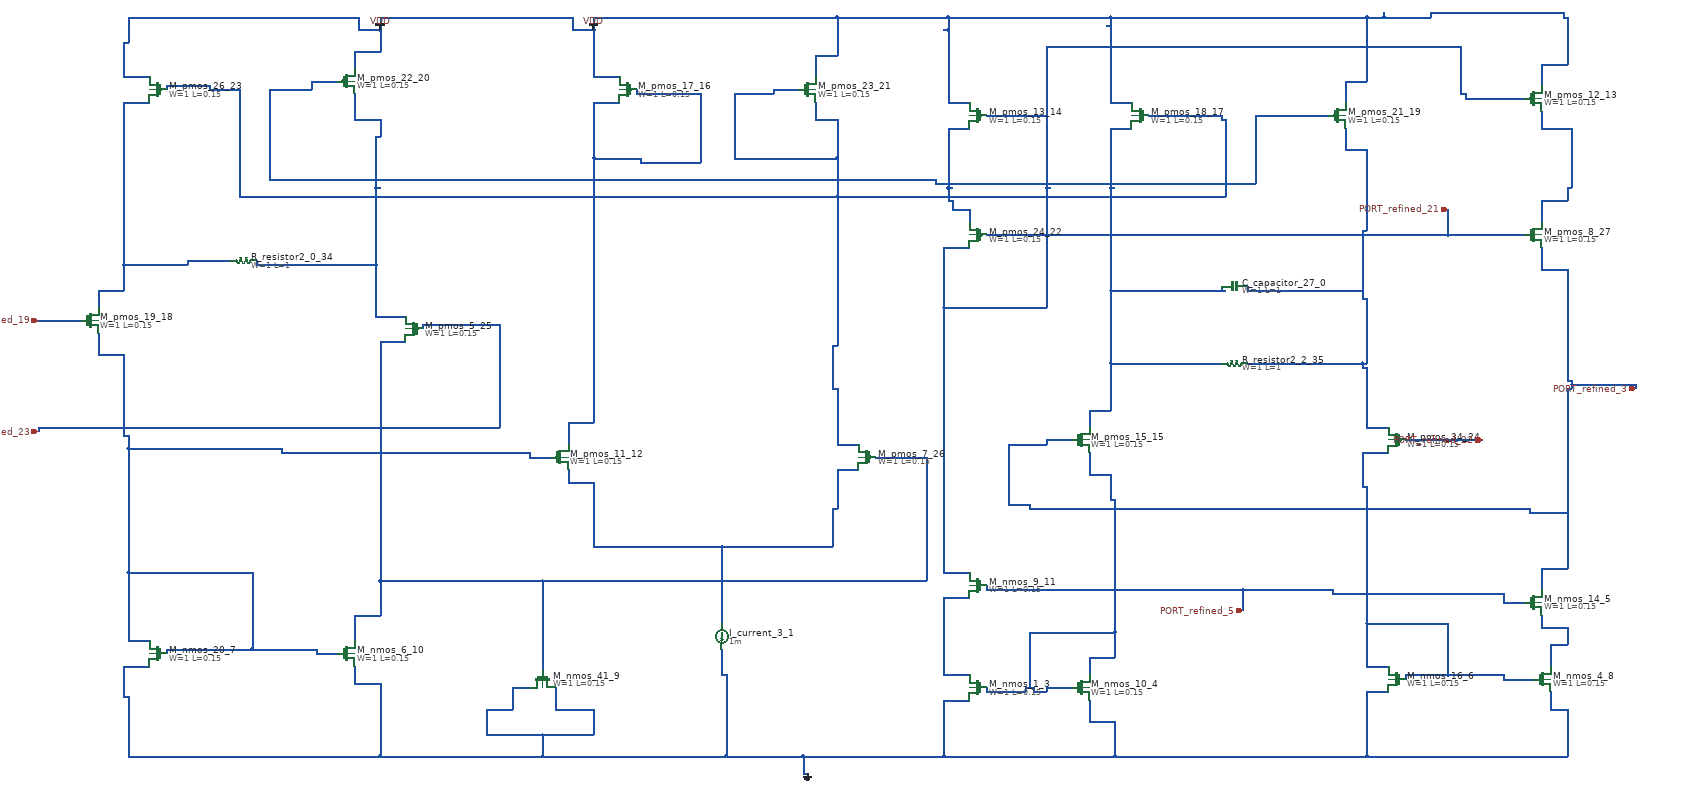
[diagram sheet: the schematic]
v {xschem version=3.4.8 file_version=1.2}
G {}
K {}
V {}
S {}
E {}
C {sky130_fd_pr/cap_mim_m3_1.sym} 2920 760 1 0 {name="C_capacitor_27_0" model=cap_mim_m3_1 W=1 L=1 MF=1 spiceprefix=X}
C {devices/isource.sym} 1720 1580 0 0 {name="I_current_3_1" value=1m}
C {devices/gnd.sym} 1920 1900 0 0 {name="l_gnd_28_2" lab="GND"}
C {sky130_fd_pr/nfet3_01v8.sym} 2320 1700 0 1 {name="M_nmos_1_3"
W=1
L=0.15
body=GND
nf=1
mult=1
ad="expr('int((@nf + 1)/2) * @W / @nf * 0.29')"
pd="expr('2*int((@nf + 1)/2) * (@W / @nf + 0.29)')"
as="expr('int((@nf + 2)/2) * @W / @nf * 0.29')"
ps="expr('2*int((@nf + 2)/2) * (@W / @nf + 0.29)')"
nrd="expr('0.29 / @W ')" nrs="expr('0.29 / @W ')"
sa=0 sb=0 sd=0
model=nfet_01v8
spiceprefix=X
}
C {sky130_fd_pr/nfet3_01v8.sym} 2560 1700 0 0 {name="M_nmos_10_4"
W=1
L=0.15
body=GND
nf=1
mult=1
ad="expr('int((@nf + 1)/2) * @W / @nf * 0.29')"
pd="expr('2*int((@nf + 1)/2) * (@W / @nf + 0.29)')"
as="expr('int((@nf + 2)/2) * @W / @nf * 0.29')"
ps="expr('2*int((@nf + 2)/2) * (@W / @nf + 0.29)')"
nrd="expr('0.29 / @W ')" nrs="expr('0.29 / @W ')"
sa=0 sb=0 sd=0
model=nfet_01v8
spiceprefix=X
}
C {sky130_fd_pr/nfet3_01v8.sym} 3620 1500 0 0 {name="M_nmos_14_5"
W=1
L=0.15
body=GND
nf=1
mult=1
ad="expr('int((@nf + 1)/2) * @W / @nf * 0.29')"
pd="expr('2*int((@nf + 1)/2) * (@W / @nf + 0.29)')"
as="expr('int((@nf + 2)/2) * @W / @nf * 0.29')"
ps="expr('2*int((@nf + 2)/2) * (@W / @nf + 0.29)')"
nrd="expr('0.29 / @W ')" nrs="expr('0.29 / @W ')"
sa=0 sb=0 sd=0
model=nfet_01v8
spiceprefix=X
}
C {sky130_fd_pr/nfet3_01v8.sym} 3300 1680 0 1 {name="M_nmos_16_6"
W=1
L=0.15
body=GND
nf=1
mult=1
ad="expr('int((@nf + 1)/2) * @W / @nf * 0.29')"
pd="expr('2*int((@nf + 1)/2) * (@W / @nf + 0.29)')"
as="expr('int((@nf + 2)/2) * @W / @nf * 0.29')"
ps="expr('2*int((@nf + 2)/2) * (@W / @nf + 0.29)')"
nrd="expr('0.29 / @W ')" nrs="expr('0.29 / @W ')"
sa=0 sb=0 sd=0
model=nfet_01v8
spiceprefix=X
}
C {sky130_fd_pr/nfet3_01v8.sym} 400 1620 0 1 {name="M_nmos_20_7"
W=1
L=0.15
body=GND
nf=1
mult=1
ad="expr('int((@nf + 1)/2) * @W / @nf * 0.29')"
pd="expr('2*int((@nf + 1)/2) * (@W / @nf + 0.29)')"
as="expr('int((@nf + 2)/2) * @W / @nf * 0.29')"
ps="expr('2*int((@nf + 2)/2) * (@W / @nf + 0.29)')"
nrd="expr('0.29 / @W ')" nrs="expr('0.29 / @W ')"
sa=0 sb=0 sd=0
model=nfet_01v8
spiceprefix=X
}
C {sky130_fd_pr/nfet3_01v8.sym} 3640 1680 0 0 {name="M_nmos_4_8"
W=1
L=0.15
body=GND
nf=1
mult=1
ad="expr('int((@nf + 1)/2) * @W / @nf * 0.29')"
pd="expr('2*int((@nf + 1)/2) * (@W / @nf + 0.29)')"
as="expr('int((@nf + 2)/2) * @W / @nf * 0.29')"
ps="expr('2*int((@nf + 2)/2) * (@W / @nf + 0.29)')"
nrd="expr('0.29 / @W ')" nrs="expr('0.29 / @W ')"
sa=0 sb=0 sd=0
model=nfet_01v8
spiceprefix=X
}
C {sky130_fd_pr/nfet3_01v8.sym} 1300 1680 1 0 {name="M_nmos_41_9"
W=1
L=0.15
body=GND
nf=1
mult=1
ad="expr('int((@nf + 1)/2) * @W / @nf * 0.29')"
pd="expr('2*int((@nf + 1)/2) * (@W / @nf + 0.29)')"
as="expr('int((@nf + 2)/2) * @W / @nf * 0.29')"
ps="expr('2*int((@nf + 2)/2) * (@W / @nf + 0.29)')"
nrd="expr('0.29 / @W ')" nrs="expr('0.29 / @W ')"
sa=0 sb=0 sd=0
model=nfet_01v8
spiceprefix=X
}
C {sky130_fd_pr/nfet3_01v8.sym} 840 1620 0 0 {name="M_nmos_6_10"
W=1
L=0.15
body=GND
nf=1
mult=1
ad="expr('int((@nf + 1)/2) * @W / @nf * 0.29')"
pd="expr('2*int((@nf + 1)/2) * (@W / @nf + 0.29)')"
as="expr('int((@nf + 2)/2) * @W / @nf * 0.29')"
ps="expr('2*int((@nf + 2)/2) * (@W / @nf + 0.29)')"
nrd="expr('0.29 / @W ')" nrs="expr('0.29 / @W ')"
sa=0 sb=0 sd=0
model=nfet_01v8
spiceprefix=X
}
C {sky130_fd_pr/nfet3_01v8.sym} 2320 1460 0 1 {name="M_nmos_9_11"
W=1
L=0.15
body=GND
nf=1
mult=1
ad="expr('int((@nf + 1)/2) * @W / @nf * 0.29')"
pd="expr('2*int((@nf + 1)/2) * (@W / @nf + 0.29)')"
as="expr('int((@nf + 2)/2) * @W / @nf * 0.29')"
ps="expr('2*int((@nf + 2)/2) * (@W / @nf + 0.29)')"
nrd="expr('0.29 / @W ')" nrs="expr('0.29 / @W ')"
sa=0 sb=0 sd=0
model=nfet_01v8
spiceprefix=X
}
C {sky130_fd_pr/pfet3_01v8.sym} 1340 1160 0 0 {name="M_pmos_11_12"
W=1
L=0.15
body=VDD
nf=1
mult=1
ad="expr('int((@nf + 1)/2) * @W / @nf * 0.29')"
pd="expr('2*int((@nf + 1)/2) * (@W / @nf + 0.29)')"
as="expr('int((@nf + 2)/2) * @W / @nf * 0.29')"
ps="expr('2*int((@nf + 2)/2) * (@W / @nf + 0.29)')"
nrd="expr('0.29 / @W ')" nrs="expr('0.29 / @W ')"
sa=0 sb=0 sd=0
model=pfet_01v8
spiceprefix=X
}
C {sky130_fd_pr/pfet3_01v8.sym} 3620 320 0 0 {name="M_pmos_12_13"
W=1
L=0.15
body=VDD
nf=1
mult=1
ad="expr('int((@nf + 1)/2) * @W / @nf * 0.29')"
pd="expr('2*int((@nf + 1)/2) * (@W / @nf + 0.29)')"
as="expr('int((@nf + 2)/2) * @W / @nf * 0.29')"
ps="expr('2*int((@nf + 2)/2) * (@W / @nf + 0.29)')"
nrd="expr('0.29 / @W ')" nrs="expr('0.29 / @W ')"
sa=0 sb=0 sd=0
model=pfet_01v8
spiceprefix=X
}
C {sky130_fd_pr/pfet3_01v8.sym} 2320 360 0 1 {name="M_pmos_13_14"
W=1
L=0.15
body=VDD
nf=1
mult=1
ad="expr('int((@nf + 1)/2) * @W / @nf * 0.29')"
pd="expr('2*int((@nf + 1)/2) * (@W / @nf + 0.29)')"
as="expr('int((@nf + 2)/2) * @W / @nf * 0.29')"
ps="expr('2*int((@nf + 2)/2) * (@W / @nf + 0.29)')"
nrd="expr('0.29 / @W ')" nrs="expr('0.29 / @W ')"
sa=0 sb=0 sd=0
model=pfet_01v8
spiceprefix=X
}
C {sky130_fd_pr/pfet3_01v8.sym} 2560 1120 0 0 {name="M_pmos_15_15"
W=1
L=0.15
body=VDD
nf=1
mult=1
ad="expr('int((@nf + 1)/2) * @W / @nf * 0.29')"
pd="expr('2*int((@nf + 1)/2) * (@W / @nf + 0.29)')"
as="expr('int((@nf + 2)/2) * @W / @nf * 0.29')"
ps="expr('2*int((@nf + 2)/2) * (@W / @nf + 0.29)')"
nrd="expr('0.29 / @W ')" nrs="expr('0.29 / @W ')"
sa=0 sb=0 sd=0
model=pfet_01v8
spiceprefix=X
}
C {sky130_fd_pr/pfet3_01v8.sym} 1500 300 0 1 {name="M_pmos_17_16"
W=1
L=0.15
body=VDD
nf=1
mult=1
ad="expr('int((@nf + 1)/2) * @W / @nf * 0.29')"
pd="expr('2*int((@nf + 1)/2) * (@W / @nf + 0.29)')"
as="expr('int((@nf + 2)/2) * @W / @nf * 0.29')"
ps="expr('2*int((@nf + 2)/2) * (@W / @nf + 0.29)')"
nrd="expr('0.29 / @W ')" nrs="expr('0.29 / @W ')"
sa=0 sb=0 sd=0
model=pfet_01v8
spiceprefix=X
}
C {sky130_fd_pr/pfet3_01v8.sym} 2700 360 0 1 {name="M_pmos_18_17"
W=1
L=0.15
body=VDD
nf=1
mult=1
ad="expr('int((@nf + 1)/2) * @W / @nf * 0.29')"
pd="expr('2*int((@nf + 1)/2) * (@W / @nf + 0.29)')"
as="expr('int((@nf + 2)/2) * @W / @nf * 0.29')"
ps="expr('2*int((@nf + 2)/2) * (@W / @nf + 0.29)')"
nrd="expr('0.29 / @W ')" nrs="expr('0.29 / @W ')"
sa=0 sb=0 sd=0
model=pfet_01v8
spiceprefix=X
}
C {sky130_fd_pr/pfet3_01v8.sym} 240 840 0 0 {name="M_pmos_19_18"
W=1
L=0.15
body=VDD
nf=1
mult=1
ad="expr('int((@nf + 1)/2) * @W / @nf * 0.29')"
pd="expr('2*int((@nf + 1)/2) * (@W / @nf + 0.29)')"
as="expr('int((@nf + 2)/2) * @W / @nf * 0.29')"
ps="expr('2*int((@nf + 2)/2) * (@W / @nf + 0.29)')"
nrd="expr('0.29 / @W ')" nrs="expr('0.29 / @W ')"
sa=0 sb=0 sd=0
model=pfet_01v8
spiceprefix=X
}
C {sky130_fd_pr/pfet3_01v8.sym} 3160 360 0 0 {name="M_pmos_21_19"
W=1
L=0.15
body=VDD
nf=1
mult=1
ad="expr('int((@nf + 1)/2) * @W / @nf * 0.29')"
pd="expr('2*int((@nf + 1)/2) * (@W / @nf + 0.29)')"
as="expr('int((@nf + 2)/2) * @W / @nf * 0.29')"
ps="expr('2*int((@nf + 2)/2) * (@W / @nf + 0.29)')"
nrd="expr('0.29 / @W ')" nrs="expr('0.29 / @W ')"
sa=0 sb=0 sd=0
model=pfet_01v8
spiceprefix=X
}
C {sky130_fd_pr/pfet3_01v8.sym} 840 280 0 0 {name="M_pmos_22_20"
W=1
L=0.15
body=VDD
nf=1
mult=1
ad="expr('int((@nf + 1)/2) * @W / @nf * 0.29')"
pd="expr('2*int((@nf + 1)/2) * (@W / @nf + 0.29)')"
as="expr('int((@nf + 2)/2) * @W / @nf * 0.29')"
ps="expr('2*int((@nf + 2)/2) * (@W / @nf + 0.29)')"
nrd="expr('0.29 / @W ')" nrs="expr('0.29 / @W ')"
sa=0 sb=0 sd=0
model=pfet_01v8
spiceprefix=X
}
C {sky130_fd_pr/pfet3_01v8.sym} 1920 300 0 0 {name="M_pmos_23_21"
W=1
L=0.15
body=VDD
nf=1
mult=1
ad="expr('int((@nf + 1)/2) * @W / @nf * 0.29')"
pd="expr('2*int((@nf + 1)/2) * (@W / @nf + 0.29)')"
as="expr('int((@nf + 2)/2) * @W / @nf * 0.29')"
ps="expr('2*int((@nf + 2)/2) * (@W / @nf + 0.29)')"
nrd="expr('0.29 / @W ')" nrs="expr('0.29 / @W ')"
sa=0 sb=0 sd=0
model=pfet_01v8
spiceprefix=X
}
C {sky130_fd_pr/pfet3_01v8.sym} 2320 640 0 1 {name="M_pmos_24_22"
W=1
L=0.15
body=VDD
nf=1
mult=1
ad="expr('int((@nf + 1)/2) * @W / @nf * 0.29')"
pd="expr('2*int((@nf + 1)/2) * (@W / @nf + 0.29)')"
as="expr('int((@nf + 2)/2) * @W / @nf * 0.29')"
ps="expr('2*int((@nf + 2)/2) * (@W / @nf + 0.29)')"
nrd="expr('0.29 / @W ')" nrs="expr('0.29 / @W ')"
sa=0 sb=0 sd=0
model=pfet_01v8
spiceprefix=X
}
C {sky130_fd_pr/pfet3_01v8.sym} 400 300 0 1 {name="M_pmos_26_23"
W=1
L=0.15
body=VDD
nf=1
mult=1
ad="expr('int((@nf + 1)/2) * @W / @nf * 0.29')"
pd="expr('2*int((@nf + 1)/2) * (@W / @nf + 0.29)')"
as="expr('int((@nf + 2)/2) * @W / @nf * 0.29')"
ps="expr('2*int((@nf + 2)/2) * (@W / @nf + 0.29)')"
nrd="expr('0.29 / @W ')" nrs="expr('0.29 / @W ')"
sa=0 sb=0 sd=0
model=pfet_01v8
spiceprefix=X
}
C {sky130_fd_pr/pfet3_01v8.sym} 3300 1120 0 1 {name="M_pmos_34_24"
W=1
L=0.15
body=VDD
nf=1
mult=1
ad="expr('int((@nf + 1)/2) * @W / @nf * 0.29')"
pd="expr('2*int((@nf + 1)/2) * (@W / @nf + 0.29)')"
as="expr('int((@nf + 2)/2) * @W / @nf * 0.29')"
ps="expr('2*int((@nf + 2)/2) * (@W / @nf + 0.29)')"
nrd="expr('0.29 / @W ')" nrs="expr('0.29 / @W ')"
sa=0 sb=0 sd=0
model=pfet_01v8
spiceprefix=X
}
C {sky130_fd_pr/pfet3_01v8.sym} 1000 860 0 1 {name="M_pmos_5_25"
W=1
L=0.15
body=VDD
nf=1
mult=1
ad="expr('int((@nf + 1)/2) * @W / @nf * 0.29')"
pd="expr('2*int((@nf + 1)/2) * (@W / @nf + 0.29)')"
as="expr('int((@nf + 2)/2) * @W / @nf * 0.29')"
ps="expr('2*int((@nf + 2)/2) * (@W / @nf + 0.29)')"
nrd="expr('0.29 / @W ')" nrs="expr('0.29 / @W ')"
sa=0 sb=0 sd=0
model=pfet_01v8
spiceprefix=X
}
C {sky130_fd_pr/pfet3_01v8.sym} 2060 1160 0 1 {name="M_pmos_7_26"
W=1
L=0.15
body=VDD
nf=1
mult=1
ad="expr('int((@nf + 1)/2) * @W / @nf * 0.29')"
pd="expr('2*int((@nf + 1)/2) * (@W / @nf + 0.29)')"
as="expr('int((@nf + 2)/2) * @W / @nf * 0.29')"
ps="expr('2*int((@nf + 2)/2) * (@W / @nf + 0.29)')"
nrd="expr('0.29 / @W ')" nrs="expr('0.29 / @W ')"
sa=0 sb=0 sd=0
model=pfet_01v8
spiceprefix=X
}
C {sky130_fd_pr/pfet3_01v8.sym} 3620 640 0 0 {name="M_pmos_8_27"
W=1
L=0.15
body=VDD
nf=1
mult=1
ad="expr('int((@nf + 1)/2) * @W / @nf * 0.29')"
pd="expr('2*int((@nf + 1)/2) * (@W / @nf + 0.29)')"
as="expr('int((@nf + 2)/2) * @W / @nf * 0.29')"
ps="expr('2*int((@nf + 2)/2) * (@W / @nf + 0.29)')"
nrd="expr('0.29 / @W ')" nrs="expr('0.29 / @W ')"
sa=0 sb=0 sd=0
model=pfet_01v8
spiceprefix=X
}
C {devices/ipin.sym} 2940 1520 0 0 {name="p_port_25_28" lab="PORT_refined_5"}
C {devices/ipin.sym} 120 840 0 0 {name="p_port_29_29" lab="PORT_refined_19"}
C {devices/ipin.sym} 120 1100 0 0 {name="p_port_30_30" lab="PORT_refined_23"}
C {devices/ipin.sym} 3420 580 0 0 {name="p_port_31_31" lab="PORT_refined_21"}
C {devices/ipin.sym} 3860 1000 0 0 {name="p_port_32_32" lab="PORT_refined_3"}
C {devices/ipin.sym} 3500 1120 0 0 {name="p_port_33_33" lab="PORT_refined_22"}
C {sky130_fd_pr/res_generic_po.sym} 600 700 1 0 {name="R_resistor2_0_34"
W=1
L=1
model=res_generic_po
spiceprefix=X
mult=1}
C {sky130_fd_pr/res_generic_po.sym} 2920 940 1 0 {name="R_resistor2_2_35"
W=1
L=1
model=res_generic_po
spiceprefix=X
mult=1}
C {devices/vdd.sym} 1420 160 0 0 {name="l_vdd_38_36" lab="VDD"}
C {devices/vdd.sym} 920 160 0 0 {name="l_vdd_40_37" lab="VDD"}
N 2580 1050 2630 1050 {}
N 2630 940 2890 940 {}
N 2630 770 2890 770 {}
N 2890 770 2900 770 {}
N 2630 530 2640 530 {}
N 2630 390 2680 390 {}
N 2580 1090 2580 1050 {}
N 2630 1050 2630 940 {}
N 2630 940 2630 770 {}
N 2630 770 2630 530 {}
N 2630 530 2630 390 {}
N 2890 770 2890 760 {}
N 3230 1090 3280 1090 {}
N 3220 950 3230 950 {}
N 2950 940 3220 940 {}
N 3220 940 3230 940 {}
N 3220 790 3230 790 {}
N 2950 770 3220 770 {}
N 3220 630 3230 630 {}
N 3180 440 3230 440 {}
N 2950 770 2950 760 {}
N 3180 440 3180 390 {}
N 3220 950 3220 940 {}
N 3220 790 3220 770 {}
N 3220 770 3220 630 {}
N 3230 1090 3230 950 {}
N 3230 940 3230 790 {}
N 3230 630 3230 440 {}
N 2240 1670 2300 1670 {}
N 2240 1490 2300 1490 {}
N 2240 1670 2240 1490 {}
N 2240 1430 2300 1430 {}
N 2240 810 2480 810 {}
N 2240 670 2300 670 {}
N 2480 530 2490 530 {}
N 2340 360 2480 360 {}
N 3460 320 3600 320 {}
N 3450 310 3460 310 {}
N 2480 200 3450 200 {}
N 2240 1430 2240 810 {}
N 2240 810 2240 670 {}
N 2480 810 2480 530 {}
N 2480 530 2480 360 {}
N 2480 360 2480 200 {}
N 3450 310 3450 200 {}
N 3460 320 3460 310 {}
N 1360 1080 1420 1080 {}
N 2220 520 2970 520 {}
N 660 510 1420 510 {}
N 1420 510 2220 510 {}
N 1530 470 1670 470 {}
N 1420 460 1530 460 {}
N 2970 360 3140 360 {}
N 1420 330 1480 330 {}
N 1520 310 1670 310 {}
N 660 300 760 300 {}
N 760 280 820 280 {}
N 660 510 660 300 {}
N 760 300 760 280 {}
N 1360 1130 1360 1080 {}
N 1420 1080 1420 510 {}
N 1420 510 1420 460 {}
N 1420 460 1420 330 {}
N 1520 310 1520 300 {}
N 1530 470 1530 460 {}
N 1670 470 1670 310 {}
N 2220 520 2220 510 {}
N 2970 520 2970 360 {}
N 1420 1370 1720 1370 {}
N 1720 1370 1980 1370 {}
N 1980 1280 1990 1280 {}
N 1360 1220 1420 1220 {}
N 1990 1190 2040 1190 {}
N 1360 1220 1360 1190 {}
N 1420 1370 1420 1220 {}
N 1720 1550 1720 1370 {}
N 1980 1370 1980 1280 {}
N 1990 1280 1990 1190 {}
N 2250 330 2300 330 {}
N 2630 330 2680 330 {}
N 3180 280 3230 280 {}
N 320 270 380 270 {}
N 1420 270 1480 270 {}
N 3640 240 3700 240 {}
N 1940 220 1990 220 {}
N 860 210 920 210 {}
N 320 190 330 190 {}
N 870 160 920 160 {}
N 1370 160 1420 160 {}
N 2240 160 2250 160 {}
N 2620 150 2630 150 {}
N 330 130 870 130 {}
N 920 130 1370 130 {}
N 1420 130 1990 130 {}
N 1990 130 2250 130 {}
N 2250 130 2630 130 {}
N 2630 130 3230 130 {}
N 3230 130 3270 130 {}
N 3270 130 3380 130 {}
N 3690 130 3700 130 {}
N 3380 120 3690 120 {}
N 320 270 320 190 {}
N 330 190 330 130 {}
N 860 250 860 210 {}
N 870 160 870 130 {}
N 920 210 920 160 {}
N 920 160 920 130 {}
N 1370 160 1370 130 {}
N 1420 270 1420 160 {}
N 1420 160 1420 130 {}
N 1940 270 1940 220 {}
N 1990 220 1990 130 {}
N 2250 330 2250 160 {}
N 2250 160 2250 130 {}
N 2630 330 2630 150 {}
N 2630 150 2630 130 {}
N 3180 330 3180 280 {}
N 3230 280 3230 130 {}
N 3270 130 3270 120 {}
N 3380 130 3380 120 {}
N 3640 290 3640 240 {}
N 3690 130 3690 120 {}
N 3700 240 3700 130 {}
N 3640 560 3700 560 {}
N 3700 530 3710 530 {}
N 3640 390 3710 390 {}
N 3640 610 3640 560 {}
N 3640 390 3640 350 {}
N 3700 560 3700 530 {}
N 3710 530 3710 390 {}
N 2260 580 2300 580 {}
N 2250 560 2260 560 {}
N 2250 530 2260 530 {}
N 2250 390 2300 390 {}
N 2250 560 2250 530 {}
N 2250 530 2250 390 {}
N 2260 580 2260 560 {}
N 2300 610 2300 580 {}
N 1990 1130 2040 1130 {}
N 1980 1000 1990 1000 {}
N 1980 900 1990 900 {}
N 590 550 1990 550 {}
N 1990 550 2900 550 {}
N 1750 460 1990 460 {}
N 1940 370 1990 370 {}
N 2890 370 2900 370 {}
N 2720 360 2890 360 {}
N 1750 310 1840 310 {}
N 520 300 590 300 {}
N 1840 300 1900 300 {}
N 420 290 520 290 {}
N 420 300 420 290 {}
N 520 300 520 290 {}
N 590 550 590 300 {}
N 1750 460 1750 310 {}
N 1840 310 1840 300 {}
N 1940 370 1940 330 {}
N 1980 1000 1980 900 {}
N 1990 1130 1990 1000 {}
N 1990 900 1990 550 {}
N 1990 550 1990 460 {}
N 1990 460 1990 370 {}
N 2890 370 2890 360 {}
N 2900 550 2900 370 {}
N 260 770 320 770 {}
N 320 710 470 710 {}
N 470 700 570 700 {}
N 320 330 380 330 {}
N 260 810 260 770 {}
N 320 770 320 710 {}
N 320 710 320 330 {}
N 470 710 470 700 {}
N 110 840 120 840 {}
N 120 840 220 840 {}
N 2340 1710 2430 1710 {}
N 2450 1710 2480 1710 {}
N 2430 1700 2440 1700 {}
N 2440 1700 2450 1700 {}
N 2480 1700 2540 1700 {}
N 2580 1630 2640 1630 {}
N 2440 1570 2640 1570 {}
N 2630 1260 2640 1260 {}
N 2580 1200 2630 1200 {}
N 2340 1710 2340 1700 {}
N 2430 1710 2430 1700 {}
N 2440 1700 2440 1570 {}
N 2450 1710 2450 1700 {}
N 2480 1710 2480 1700 {}
N 2580 1670 2580 1630 {}
N 2580 1200 2580 1150 {}
N 2630 1260 2630 1200 {}
N 2640 1630 2640 1570 {}
N 2640 1570 2640 1260 {}
N 910 830 980 830 {}
N 630 710 910 710 {}
N 910 530 920 530 {}
N 910 410 920 410 {}
N 860 370 920 370 {}
N 630 710 630 700 {}
N 860 370 860 310 {}
N 910 830 910 710 {}
N 910 710 910 530 {}
N 910 530 910 410 {}
N 920 410 920 370 {}
N 2340 640 3420 640 {}
N 3420 640 3600 640 {}
N 3420 640 3420 580 {}
N 3320 1120 3500 1120 {}
N 120 1090 1200 1090 {}
N 1020 850 1200 850 {}
N 120 1100 120 1090 {}
N 1020 860 1020 850 {}
N 1200 1090 1200 850 {}
N 3640 1420 3700 1420 {}
N 3610 1290 3700 1290 {}
N 2440 1280 3610 1280 {}
N 2390 1270 2440 1270 {}
N 2390 1130 2480 1130 {}
N 2480 1120 2540 1120 {}
N 3700 1000 3710 1000 {}
N 3710 990 3860 990 {}
N 3700 980 3710 980 {}
N 3640 720 3700 720 {}
N 2390 1270 2390 1130 {}
N 2440 1280 2440 1270 {}
N 2480 1130 2480 1120 {}
N 3610 1290 3610 1280 {}
N 3640 1470 3640 1420 {}
N 3640 720 3640 670 {}
N 3700 1420 3700 1290 {}
N 3700 1290 3700 1000 {}
N 3700 980 3700 720 {}
N 3710 1000 3710 990 {}
N 3710 990 3710 980 {}
N 3860 1000 3860 990 {}
N 3660 1600 3700 1600 {}
N 3640 1560 3700 1560 {}
N 3640 1560 3640 1530 {}
N 3660 1650 3660 1600 {}
N 3700 1600 3700 1560 {}
N 3550 1500 3600 1500 {}
N 3150 1480 3550 1480 {}
N 2340 1470 2940 1470 {}
N 2940 1470 3150 1470 {}
N 2340 1470 2340 1460 {}
N 2940 1520 2940 1470 {}
N 3150 1480 3150 1470 {}
N 3550 1500 3550 1480 {}
N 1910 1900 1920 1900 {}
N 330 1860 920 1860 {}
N 920 1860 1300 1860 {}
N 1300 1860 1730 1860 {}
N 1730 1860 1910 1860 {}
N 1910 1860 2240 1860 {}
N 2240 1860 2640 1860 {}
N 2640 1860 3230 1860 {}
N 3230 1860 3700 1860 {}
N 1170 1810 1300 1810 {}
N 1300 1810 1420 1810 {}
N 2580 1780 2640 1780 {}
N 1170 1750 1230 1750 {}
N 1330 1750 1420 1750 {}
N 3660 1750 3700 1750 {}
N 2240 1730 2300 1730 {}
N 320 1720 330 1720 {}
N 3230 1710 3280 1710 {}
N 1230 1700 1270 1700 {}
N 860 1690 920 1690 {}
N 1720 1670 1730 1670 {}
N 320 1650 380 1650 {}
N 320 1720 320 1650 {}
N 330 1860 330 1720 {}
N 860 1690 860 1650 {}
N 920 1860 920 1690 {}
N 1170 1810 1170 1750 {}
N 1230 1750 1230 1700 {}
N 1300 1860 1300 1810 {}
N 1330 1750 1330 1700 {}
N 1420 1810 1420 1750 {}
N 1720 1670 1720 1610 {}
N 1730 1860 1730 1670 {}
N 1910 1900 1910 1860 {}
N 2240 1860 2240 1730 {}
N 2580 1780 2580 1730 {}
N 2640 1860 2640 1780 {}
N 3230 1860 3230 1710 {}
N 3660 1750 3660 1710 {}
N 3700 1860 3700 1750 {}
N 3550 1680 3620 1680 {}
N 3320 1670 3420 1670 {}
N 3420 1670 3550 1670 {}
N 3230 1650 3280 1650 {}
N 3230 1550 3420 1550 {}
N 3220 1230 3230 1230 {}
N 3220 1150 3280 1150 {}
N 3220 1230 3220 1150 {}
N 3230 1650 3230 1550 {}
N 3230 1550 3230 1230 {}
N 3320 1680 3320 1670 {}
N 3420 1670 3420 1550 {}
N 3550 1680 3550 1670 {}
N 770 1620 820 1620 {}
N 420 1610 620 1610 {}
N 620 1610 770 1610 {}
N 330 1590 380 1590 {}
N 330 1430 620 1430 {}
N 1270 1160 1320 1160 {}
N 690 1150 1270 1150 {}
N 330 1140 690 1140 {}
N 320 1110 330 1110 {}
N 260 920 320 920 {}
N 260 920 260 870 {}
N 320 1110 320 920 {}
N 330 1590 330 1430 {}
N 330 1430 330 1140 {}
N 330 1140 330 1110 {}
N 420 1620 420 1610 {}
N 620 1610 620 1430 {}
N 690 1150 690 1140 {}
N 770 1620 770 1610 {}
N 1270 1160 1270 1150 {}
N 860 1530 920 1530 {}
N 920 1450 1300 1450 {}
N 1300 1450 2200 1450 {}
N 2080 1160 2200 1160 {}
N 920 890 980 890 {}
N 860 1590 860 1530 {}
N 920 1530 920 1450 {}
N 920 1450 920 890 {}
N 1300 1660 1300 1450 {}
N 2200 1450 2200 1160 {}
